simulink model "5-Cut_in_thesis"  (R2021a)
settings: Solver=VariableStepAuto  StartTime=0.0  StopTime=24  RelTol=1e-3
undefined symbols (not defined in the file or in its folder): aubr, tablebr, vubr
libraries: pid_lib x5, Solver_SF x2

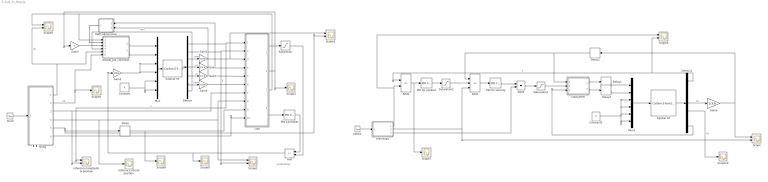
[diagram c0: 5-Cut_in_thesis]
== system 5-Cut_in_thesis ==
  note: 规划接口
  note: understeer
  Add : Sum  Inputs=-+
  Add1 : Sum  Inputs=-++
  Add2 : Sum  Inputs=-+
  Add3 : Sum
  Clock : Clock
  Clock1 : Clock
  Constant : Constant  Value=0
  Constant2 : Constant  Value=0
  Delay : Delay  DelayLength=10
  Delay1 : Delay  DelayLength=100
  Delay2 : Delay  DelayLength=10
  Delay3 : Delay  DelayLength=100
  Demux : Demux  Outputs=7
  Demux1 : Demux  Outputs=7
  EgoCar SF : Solver_SF/CarSim S-Function  Priority=1  SIMFILE=Cut_in_Ego_Car.sim
  Gain : Gain  Gain=1/3.6
  Gain1 : Gain  Gain=1/3.6
  Gain2 : Gain  Gain=pi/180
  Gain3 : Gain  Gain=180/pi
  Gain4 : Gain  Gain=pi/180
  Gain5 : Gain  Gain=-1
  Gain6 : Gain  Gain=1/3.6
  LQR : Subsystem
  MATLAB Function : MATLAB Function  TreatAsAtomicUnit=on
  Mux : Mux  Inputs=6
  Mux1 : Mux  Inputs=6
  PID Controller : pid_lib/PID Controller  Controller=PID  Form=Parallel  TimeDomain=Continuous-time  UseExternalTs=off  SampleTime=-1  IntegratorMethod=Forward Euler  FilterMethod=Forward Euler  ControllerParametersSource=internal  P=1  I=0  D=0  UseFilter=on  N=100  TunerSelectOption=Transfer Function Based (PID Tuner App)  InitialConditionSource=internal  InitialConditionForIntegrator=0  InitialConditionForFilter=0  DifferentiatorICPrevScaledInput=0  ExternalReset=none  TrackingMode=off  Kt=1  LimitOutput=off  SatLimitsSource=internal  UpperSaturationLimit=inf  LowerSaturationLimit=-inf  LinearizeAsGain=on  AntiWindupMode=none  Kb=1  POutMin=[]  POutMax=[]  IOutMin=[]  IOutMax=[]  DOutMin=[]  DOutMax=[]  NOutMin=[]  NOutMax=[]  SumOutMin=[]  SumOutMax=[]  SaturationOutMin=[]  SaturationOutMax=[]  PParamMin=[]  PParamMax=[]  IParamMin=[]  IParamMax=[]  DParamMin=[]  DParamMax=[]  NParamMin=[]  NParamMax=[]  KbParamMin=[]  KbParamMax=[]  KtParamMin=[]  KtParamMax=[]  KbOutMin=[]  KbOutMax=[]  KtOutMin=[]  KtOutMax=[]  IntegratorOutMin=[]  IntegratorOutMax=[]  FilterOutMin=[]  FilterOutMax=[]  SumI1OutMin=[]  SumI1OutMax=[]  SumI2OutMin=[]  SumI2OutMax=[]  SumI3OutMin=[]  SumI3OutMax=[]  SumI4OutMin=[]  SumI4OutMax=[]  SumDOutMin=[]  SumDOutMax=[]  DifferentiatorOutMin=[]  DifferentiatorOutMax=[]  FilterDiffOutCoefMin=[]  FilterDiffOutCoefMax=[]  ReciprocalOutMin=[]  ReciprocalOutMax=[]  SumDenOutMin=[]  SumDenOutMax=[]  SumNumOutMin=[]  SumNumOutMax=[]  DivideOutMin=[]  DivideOutMax=[]  UdiffTsProdOutMin=[]  UdiffTsProdOutMax=[]  NTsProdOutMin=[]  NTsProdOutMax=[]  UintegralTsProdOutMin=[]  UintegralTsProdOutMax=[]  UngainTsProdOutMin=[]  UngainTsProdOutMax=[]  IntegratorContinuousStateAttributes=''  IntegratorStateMustResolveToSignalObject=off  IntegratorRTWStateStorageClass=Auto  FilterContinuousStateAttributes=''  FilterStateMustResolveToSignalObject=off  FilterRTWStateStorageClass=Auto  ParallelPVariant=InternalParameters  IdealPVariant=Disabled  IVariant=InternalParameters  DVariant=InternalParameters  IntegratorVariant=Continuous  SatVariant=Disabled  AWVariant=Passthrough  PCopyVariant=Disabled  TRVariant=Disabled  FdbkBlocksVariant=Forward  IdealPFdbkVariant=Disabled  SatFdbkVariant=Disabled  DerivativeFilterVariant=ContFilter  NVariant=InternalParameters  NCopyVariant=Disabled  FilterICVariant=InternalICsFilter  IntegratorICVariant=InternalICs  ExternalResetVariant=Disabled  TRSumVariant=Passthrough  SumFdbkVariant=Disabled  SumVariant=Sum_PID  TsampFilterVariant=InternalTs  TsampNgainVariant=Passthrough  TsampIntegralVariant=Passthrough  ExternalSaturationOutDataTypeStr=Inherit: Same as second input
  PID for position : pid_lib/PID Controller  Controller=PID  Form=Parallel  TimeDomain=Continuous-time  UseExternalTs=off  SampleTime=-1  IntegratorMethod=Forward Euler  FilterMethod=Forward Euler  ControllerParametersSource=internal  P=2  I=0  D=0.1  UseFilter=on  N=30  TunerSelectOption=Transfer Function Based (PID Tuner App)  InitialConditionSource=internal  InitialConditionForIntegrator=0  InitialConditionForFilter=0  DifferentiatorICPrevScaledInput=0  ExternalReset=none  TrackingMode=off  Kt=1  LimitOutput=off  SatLimitsSource=internal  UpperSaturationLimit=inf  LowerSaturationLimit=-inf  LinearizeAsGain=on  AntiWindupMode=none  Kb=1  POutMin=[]  POutMax=[]  IOutMin=[]  IOutMax=[]  DOutMin=[]  DOutMax=[]  NOutMin=[]  NOutMax=[]  SumOutMin=[]  SumOutMax=[]  SaturationOutMin=[]  SaturationOutMax=[]  PParamMin=[]  PParamMax=[]  IParamMin=[]  IParamMax=[]  DParamMin=[]  DParamMax=[]  NParamMin=[]  NParamMax=[]  KbParamMin=[]  KbParamMax=[]  KtParamMin=[]  KtParamMax=[]  KbOutMin=[]  KbOutMax=[]  KtOutMin=[]  KtOutMax=[]  IntegratorOutMin=[]  IntegratorOutMax=[]  FilterOutMin=[]  FilterOutMax=[]  SumI1OutMin=[]  SumI1OutMax=[]  SumI2OutMin=[]  SumI2OutMax=[]  SumI3OutMin=[]  SumI3OutMax=[]  SumI4OutMin=[]  SumI4OutMax=[]  SumDOutMin=[]  SumDOutMax=[]  DifferentiatorOutMin=[]  DifferentiatorOutMax=[]  FilterDiffOutCoefMin=[]  FilterDiffOutCoefMax=[]  ReciprocalOutMin=[]  ReciprocalOutMax=[]  SumDenOutMin=[]  SumDenOutMax=[]  SumNumOutMin=[]  SumNumOutMax=[]  DivideOutMin=[]  DivideOutMax=[]  UdiffTsProdOutMin=[]  UdiffTsProdOutMax=[]  NTsProdOutMin=[]  NTsProdOutMax=[]  UintegralTsProdOutMin=[]  UintegralTsProdOutMax=[]  UngainTsProdOutMin=[]  UngainTsProdOutMax=[]  IntegratorContinuousStateAttributes=''  IntegratorStateMustResolveToSignalObject=off  IntegratorRTWStateStorageClass=Auto  FilterContinuousStateAttributes=''  FilterStateMustResolveToSignalObject=off  FilterRTWStateStorageClass=Auto  ParallelPVariant=InternalParameters  IdealPVariant=Disabled  IVariant=InternalParameters  DVariant=InternalParameters  IntegratorVariant=Continuous  SatVariant=Disabled  AWVariant=Passthrough  PCopyVariant=Disabled  TRVariant=Disabled  FdbkBlocksVariant=Forward  IdealPFdbkVariant=Disabled  SatFdbkVariant=Disabled  DerivativeFilterVariant=ContFilter  NVariant=InternalParameters  NCopyVariant=Disabled  FilterICVariant=InternalICsFilter  IntegratorICVariant=InternalICs  ExternalResetVariant=Disabled  TRSumVariant=Passthrough  SumFdbkVariant=Disabled  SumVariant=Sum_PID  TsampFilterVariant=InternalTs  TsampNgainVariant=Passthrough  TsampIntegralVariant=Passthrough  ExternalSaturationOutDataTypeStr=Inherit: Same as second input
  PID for velocity : pid_lib/PID Controller  Controller=PID  Form=Parallel  TimeDomain=Continuous-time  UseExternalTs=off  SampleTime=-1  IntegratorMethod=Forward Euler  FilterMethod=Forward Euler  ControllerParametersSource=internal  P=1  I=0  D=0.1  UseFilter=on  N=30  TunerSelectOption=Transfer Function Based (PID Tuner App)  InitialConditionSource=internal  InitialConditionForIntegrator=0  InitialConditionForFilter=0  DifferentiatorICPrevScaledInput=0  ExternalReset=none  TrackingMode=off  Kt=1  LimitOutput=off  SatLimitsSource=internal  UpperSaturationLimit=inf  LowerSaturationLimit=-inf  LinearizeAsGain=on  AntiWindupMode=none  Kb=1  POutMin=[]  POutMax=[]  IOutMin=[]  IOutMax=[]  DOutMin=[]  DOutMax=[]  NOutMin=[]  NOutMax=[]  SumOutMin=[]  SumOutMax=[]  SaturationOutMin=[]  SaturationOutMax=[]  PParamMin=[]  PParamMax=[]  IParamMin=[]  IParamMax=[]  DParamMin=[]  DParamMax=[]  NParamMin=[]  NParamMax=[]  KbParamMin=[]  KbParamMax=[]  KtParamMin=[]  KtParamMax=[]  KbOutMin=[]  KbOutMax=[]  KtOutMin=[]  KtOutMax=[]  IntegratorOutMin=[]  IntegratorOutMax=[]  FilterOutMin=[]  FilterOutMax=[]  SumI1OutMin=[]  SumI1OutMax=[]  SumI2OutMin=[]  SumI2OutMax=[]  SumI3OutMin=[]  SumI3OutMax=[]  SumI4OutMin=[]  SumI4OutMax=[]  SumDOutMin=[]  SumDOutMax=[]  DifferentiatorOutMin=[]  DifferentiatorOutMax=[]  FilterDiffOutCoefMin=[]  FilterDiffOutCoefMax=[]  ReciprocalOutMin=[]  ReciprocalOutMax=[]  SumDenOutMin=[]  SumDenOutMax=[]  SumNumOutMin=[]  SumNumOutMax=[]  DivideOutMin=[]  DivideOutMax=[]  UdiffTsProdOutMin=[]  UdiffTsProdOutMax=[]  NTsProdOutMin=[]  NTsProdOutMax=[]  UintegralTsProdOutMin=[]  UintegralTsProdOutMax=[]  UngainTsProdOutMin=[]  UngainTsProdOutMax=[]  IntegratorContinuousStateAttributes=''  IntegratorStateMustResolveToSignalObject=off  IntegratorRTWStateStorageClass=Auto  FilterContinuousStateAttributes=''  FilterStateMustResolveToSignalObject=off  FilterRTWStateStorageClass=Auto  ParallelPVariant=InternalParameters  IdealPVariant=Disabled  IVariant=InternalParameters  DVariant=InternalParameters  IntegratorVariant=Continuous  SatVariant=Disabled  AWVariant=Passthrough  PCopyVariant=Disabled  TRVariant=Disabled  FdbkBlocksVariant=Forward  IdealPFdbkVariant=Disabled  SatFdbkVariant=Disabled  DerivativeFilterVariant=ContFilter  NVariant=InternalParameters  NCopyVariant=Disabled  FilterICVariant=InternalICsFilter  IntegratorICVariant=InternalICs  ExternalResetVariant=Disabled  TRSumVariant=Passthrough  SumFdbkVariant=Disabled  SumVariant=Sum_PID  TsampFilterVariant=InternalTs  TsampNgainVariant=Passthrough  TsampIntegralVariant=Passthrough  ExternalSaturationOutDataTypeStr=Inherit: Same as second input
  Saturation : Saturate  UpperLimit=1  LowerLimit=-1
  Saturation1 : Saturate  UpperLimit=5  LowerLimit=-8
  Saturation2 : Saturate  UpperLimit=10  LowerLimit=-10
  Scope{,1..2,5..6} (5 alike) : Scope  NumInputPorts=2
  Scope{3..4,7..10} (6 alike) : Scope
  SideCar SF : Solver_SF/CarSim S-Function  Priority=1  SIMFILE=SideCar.sim
  Subsystem : Subsystem
  double_pid_controller : Subsystem
  planning : MATLAB Function  TreatAsAtomicUnit=on
  planning1 : MATLAB Function  TreatAsAtomicUnit=on
  reference lateral position : Scope
  reference longitudinal position : Scope  NumInputPorts=2
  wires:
  planning/6(kr) -> LQR/10(kappar)
  Demux/1 -> reference longitudinal position/1, LQR/1(x)  "x"
  LQR/4(ed) -> PID Controller/1
  Gain2/1 -> Scope2/1, LQR/3(phi)
  Demux/4 -> Gain/1  "vx"
  Demux/2 -> Scope1/2, LQR/2(y)  "y"
  PID Controller/1 -> Add/1
  Add/1 -> Scope9/1, Gain3/1
  Saturation/1 -> Add/2
  Constant/1 -> Mux/5, Mux/6
  planning/1(vp) -> Scope5/2, double_pid_controller/5(vp)  "vp"
  planning/2(ap) -> double_pid_controller/6(ap), Scope4/1  "ap"
  LQR/3(s_dot) -> Scope5/1, double_pid_controller/1(s_dot)
  LQR/1(angle) -> Saturation/1
  Clock/1 -> planning/1(t)
  LQR/2(es) -> Scope3/1, Gain5/1
  Mux/1 -> SideCar SF/1
  double_pid_controller/2(Out2) -> Mux/2
  Gain/1 -> LQR/4(vx), MATLAB Function/1(vx)
  Demux/6 -> Gain4/1  "dyaw"
  Demux/3 -> Gain2/1  "yaw"
  Gain1/1 -> LQR/5(vy), MATLAB Function/2(vy)
  Demux/5 -> Gain1/1  "vy"
  Demux/7 -> double_pid_controller/4(rpm)  "rpm"
  Gain4/1 -> LQR/6(phi_dot)
  double_pid_controller/1(Out1) -> Mux/1
  Gain3/1 -> Mux/4, Mux/3
  MATLAB Function/1(v) -> double_pid_controller/2(v)
  Gain5/1 -> double_pid_controller/3(es)
  planning/5(thetar) -> Scope2/2, Delay/1
  planning/4(yr) -> LQR/8(yr), Scope1/1, reference lateral position/1
  planning/3(xr) -> reference longitudinal position/2, LQR/7(xr)
  SideCar SF/1 -> Demux/1
  Add1/1 -> PID for velocity/1
  Demux1/4 -> Gain6/1  "Vx"
  Clock1/1 -> planning1/1(t)
  Gain6/1 -> Scope/1, Delay2/1
  Delay2/1 -> Add1/1, Subsystem/1(v)
  Mux1/1 -> EgoCar SF/1
  Constant2/1 -> Mux1/3, Mux1/4, Mux1/6, Mux1/5
  EgoCar SF/1 -> Demux1/1
  planning1/2(vp) -> Scope/2, Add1/3
  Saturation1/1 -> Subsystem/2(a)
  Demux1/7 -> Subsystem/3(rpm)
  Subsystem/1(torque) -> Delay1/1
  Subsystem/2(brake) -> Delay3/1
  Add2/1 -> Scope7/1, PID for position/1
  planning1/1(xr) -> Scope6/1, Add2/2
  Demux1/1 -> Scope6/2, Add2/1  "x"
  PID for velocity/1 -> Add3/1
  Add3/1 -> Saturation1/1
  planning1/3(ap) -> Add3/2
  PID for position/1 -> Saturation2/1
  Saturation2/1 -> Add1/2
  Delay1/1 -> Mux1/1
  Delay3/1 -> Mux1/2
  Delay/1 -> LQR/9(thetar), Scope8/1
  Demux1/5 -> Scope10/1  "vy"
  Demux1/3 -> ?  "yaw"
  Demux1/6 -> ?  "dyaw"

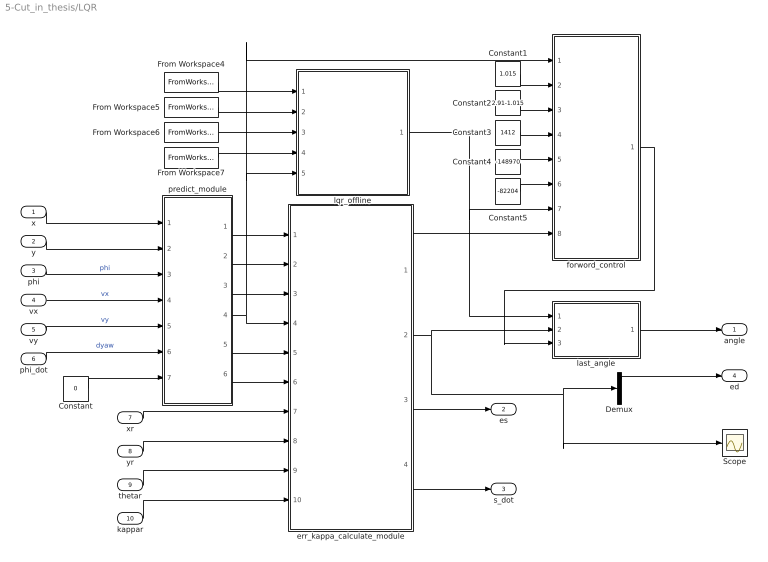
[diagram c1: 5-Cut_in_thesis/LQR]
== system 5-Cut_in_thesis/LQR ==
  x : Inport
  y : Inport  Port=2
  phi : Inport  Port=3
  vx : Inport  Port=4
  vy : Inport  Port=5
  phi_dot : Inport  Port=6
  xr : Inport  Port=7
  yr : Inport  Port=8
  thetar : Inport  Port=9
  kappar : Inport  Port=10
  Constant : Constant  Value=0
  Constant1 : Constant  Value=1.015
  Constant2 : Constant  Value=2.91-1.015
  Constant3 : Constant  Value=1412
  Constant4 : Constant  Value=-148970
  Constant5 : Constant  Value=-82204
  Demux : Demux
  From Workspace4 : FromWorkspace  VariableName=k1
  From Workspace5 : FromWorkspace  VariableName=k2
  From Workspace6 : FromWorkspace  VariableName=k3
  From Workspace7 : FromWorkspace  VariableName=k4
  Scope : Scope
  err_kappa_calculate_module : MATLAB Function  TreatAsAtomicUnit=on
  forword_control : MATLAB Function  TreatAsAtomicUnit=on
  last_angle : MATLAB Function  TreatAsAtomicUnit=on
  lqr_offline : MATLAB Function  TreatAsAtomicUnit=on
  predict_module : MATLAB Function  TreatAsAtomicUnit=on
  angle : Outport  VectorParamsAs1DForOutWhenUnconnected=off
  es : Outport  Port=2  VectorParamsAs1DForOutWhenUnconnected=off
  s_dot : Outport  Port=3  VectorParamsAs1DForOutWhenUnconnected=off
  ed : Outport  Port=4  VectorParamsAs1DForOutWhenUnconnected=off
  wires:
  From Workspace7/1 -> lqr_offline/4(k4)
  vy/1 -> predict_module/5(vy)  "vy"
  From Workspace6/1 -> lqr_offline/3(k3)
  x/1 -> predict_module/1(x)
  lqr_offline/1(k) -> last_angle/1(k), forword_control/7(k)
  predict_module/2(pre_y) -> err_kappa_calculate_module/2(y)
  err_kappa_calculate_module/1(kr) -> forword_control/8(kr)
  forword_control/1(forword_angle) -> last_angle/3(forword_angle)
  predict_module/4(pre_vx) -> lqr_offline/5(vx), forword_control/1(vx), err_kappa_calculate_module/4(vx)
  phi_dot/1 -> predict_module/6(phi_dot)  "dyaw"
  last_angle/1(angle) -> angle/1
  From Workspace5/1 -> lqr_offline/2(k2)
  vx/1 -> predict_module/4(vx)  "vx"
  y/1 -> predict_module/2(y)
  phi/1 -> predict_module/3(phi)  "phi"
  Constant/1 -> predict_module/7(ts)
  From Workspace4/1 -> lqr_offline/1(k1)
  predict_module/1(pre_x) -> err_kappa_calculate_module/1(x)
  predict_module/5(pre_vy) -> err_kappa_calculate_module/5(vy)
  predict_module/6(pre_phi_dot) -> err_kappa_calculate_module/6(phi_dot)
  predict_module/3(pre_phi) -> err_kappa_calculate_module/3(phi)
  Constant1/1 -> forword_control/2(a)
  Constant2/1 -> forword_control/3(b)
  Constant3/1 -> forword_control/4(m)
  Constant4/1 -> forword_control/5(cf)
  xr/1 -> err_kappa_calculate_module/7(xr)
  yr/1 -> err_kappa_calculate_module/8(yr)
  thetar/1 -> err_kappa_calculate_module/9(thetar)
  kappar/1 -> err_kappa_calculate_module/10(kappar)
  err_kappa_calculate_module/3(es) -> es/1
  err_kappa_calculate_module/4(s_dot) -> s_dot/1
  Constant5/1 -> forword_control/6(cr)
  Demux/1 -> ed/1
  err_kappa_calculate_module/2(err) -> Scope/1, Demux/1, last_angle/2(err)

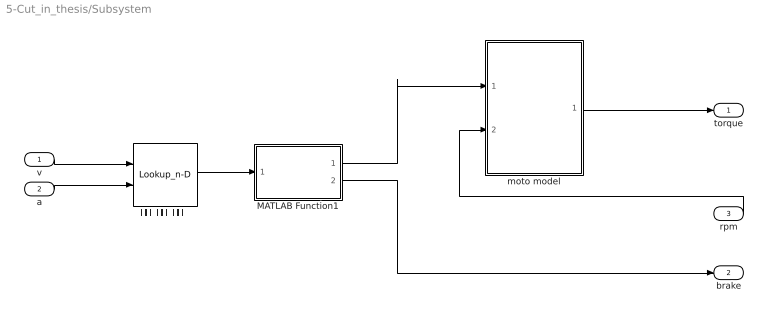
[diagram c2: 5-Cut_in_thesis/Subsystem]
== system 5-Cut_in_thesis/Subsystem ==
  v : Inport
  a : Inport  Port=2
  rpm : Inport  Port=3
  MATLAB Function1 : MATLAB Function  TreatAsAtomicUnit=on
  moto model : MATLAB Function  TreatAsAtomicUnit=on
  油门刹车合并标定表 : Lookup_n-D  BreakpointsForDimension1=vubr  BreakpointsForDimension2=aubr  Table=tablebr  InternalRulePriority=Speed  RndMeth=Simplest
  torque : Outport
  brake : Outport  Port=2
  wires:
  rpm/1 -> moto model/2(rpm)
  油门刹车合并标定表/1 -> MATLAB Function1/1(x)
  MATLAB Function1/1(thr) -> moto model/1(thr)
  MATLAB Function1/2(brake) -> brake/1
  v/1 -> 油门刹车合并标定表/1
  moto model/1(torque) -> torque/1
  a/1 -> 油门刹车合并标定表/2

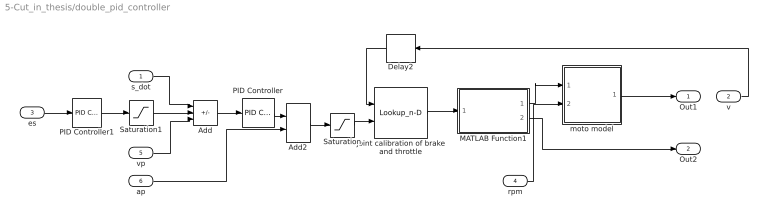
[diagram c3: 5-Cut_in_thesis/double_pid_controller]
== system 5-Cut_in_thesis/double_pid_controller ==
  s_dot : Inport
  v : Inport  Port=2
  es : Inport  Port=3
  rpm : Inport  Port=4
  vp : Inport  Port=5
  ap : Inport  Port=6
  Add : Sum  Inputs=-++
  Add2 : Sum
  Delay2 : Delay  DelayLength=1
  MATLAB Function1 : MATLAB Function  TreatAsAtomicUnit=on
  PID Controller : pid_lib/PID Controller  Controller=PID  Form=Parallel  TimeDomain=Continuous-time  UseExternalTs=off  SampleTime=-1  IntegratorMethod=Forward Euler  FilterMethod=Forward Euler  ControllerParametersSource=internal  P=3  I=0  D=0.1  UseFilter=on  N=30  TunerSelectOption=Transfer Function Based (PID Tuner App)  InitialConditionSource=internal  InitialConditionForIntegrator=0  InitialConditionForFilter=0  DifferentiatorICPrevScaledInput=0  ExternalReset=none  TrackingMode=off  Kt=1  LimitOutput=off  SatLimitsSource=internal  UpperSaturationLimit=inf  LowerSaturationLimit=-inf  LinearizeAsGain=on  AntiWindupMode=none  Kb=1  POutMin=[]  POutMax=[]  IOutMin=[]  IOutMax=[]  DOutMin=[]  DOutMax=[]  NOutMin=[]  NOutMax=[]  SumOutMin=[]  SumOutMax=[]  SaturationOutMin=[]  SaturationOutMax=[]  PParamMin=[]  PParamMax=[]  IParamMin=[]  IParamMax=[]  DParamMin=[]  DParamMax=[]  NParamMin=[]  NParamMax=[]  KbParamMin=[]  KbParamMax=[]  KtParamMin=[]  KtParamMax=[]  KbOutMin=[]  KbOutMax=[]  KtOutMin=[]  KtOutMax=[]  IntegratorOutMin=[]  IntegratorOutMax=[]  FilterOutMin=[]  FilterOutMax=[]  SumI1OutMin=[]  SumI1OutMax=[]  SumI2OutMin=[]  SumI2OutMax=[]  SumI3OutMin=[]  SumI3OutMax=[]  SumI4OutMin=[]  SumI4OutMax=[]  SumDOutMin=[]  SumDOutMax=[]  DifferentiatorOutMin=[]  DifferentiatorOutMax=[]  FilterDiffOutCoefMin=[]  FilterDiffOutCoefMax=[]  ReciprocalOutMin=[]  ReciprocalOutMax=[]  SumDenOutMin=[]  SumDenOutMax=[]  SumNumOutMin=[]  SumNumOutMax=[]  DivideOutMin=[]  DivideOutMax=[]  UdiffTsProdOutMin=[]  UdiffTsProdOutMax=[]  NTsProdOutMin=[]  NTsProdOutMax=[]  UintegralTsProdOutMin=[]  UintegralTsProdOutMax=[]  UngainTsProdOutMin=[]  UngainTsProdOutMax=[]  IntegratorContinuousStateAttributes=''  IntegratorStateMustResolveToSignalObject=off  IntegratorRTWStateStorageClass=Auto  FilterContinuousStateAttributes=''  FilterStateMustResolveToSignalObject=off  FilterRTWStateStorageClass=Auto  ParallelPVariant=InternalParameters  IdealPVariant=Disabled  IVariant=InternalParameters  DVariant=InternalParameters  IntegratorVariant=Continuous  SatVariant=Disabled  AWVariant=Passthrough  PCopyVariant=Disabled  TRVariant=Disabled  FdbkBlocksVariant=Forward  IdealPFdbkVariant=Disabled  SatFdbkVariant=Disabled  DerivativeFilterVariant=ContFilter  NVariant=InternalParameters  NCopyVariant=Disabled  FilterICVariant=InternalICsFilter  IntegratorICVariant=InternalICs  ExternalResetVariant=Disabled  TRSumVariant=Passthrough  SumFdbkVariant=Disabled  SumVariant=Sum_PID  TsampFilterVariant=InternalTs  TsampNgainVariant=Passthrough  TsampIntegralVariant=Passthrough  ExternalSaturationOutDataTypeStr=Inherit: Same as second input
  PID Controller1 : pid_lib/PID Controller  Controller=PID  Form=Parallel  TimeDomain=Continuous-time  UseExternalTs=off  SampleTime=-1  IntegratorMethod=Forward Euler  FilterMethod=Forward Euler  ControllerParametersSource=internal  P=3  I=0  D=0.1  UseFilter=on  N=30  TunerSelectOption=Transfer Function Based (PID Tuner App)  InitialConditionSource=internal  InitialConditionForIntegrator=0  InitialConditionForFilter=0  DifferentiatorICPrevScaledInput=0  ExternalReset=none  TrackingMode=off  Kt=1  LimitOutput=off  SatLimitsSource=internal  UpperSaturationLimit=inf  LowerSaturationLimit=-inf  LinearizeAsGain=on  AntiWindupMode=none  Kb=1  POutMin=[]  POutMax=[]  IOutMin=[]  IOutMax=[]  DOutMin=[]  DOutMax=[]  NOutMin=[]  NOutMax=[]  SumOutMin=[]  SumOutMax=[]  SaturationOutMin=[]  SaturationOutMax=[]  PParamMin=[]  PParamMax=[]  IParamMin=[]  IParamMax=[]  DParamMin=[]  DParamMax=[]  NParamMin=[]  NParamMax=[]  KbParamMin=[]  KbParamMax=[]  KtParamMin=[]  KtParamMax=[]  KbOutMin=[]  KbOutMax=[]  KtOutMin=[]  KtOutMax=[]  IntegratorOutMin=[]  IntegratorOutMax=[]  FilterOutMin=[]  FilterOutMax=[]  SumI1OutMin=[]  SumI1OutMax=[]  SumI2OutMin=[]  SumI2OutMax=[]  SumI3OutMin=[]  SumI3OutMax=[]  SumI4OutMin=[]  SumI4OutMax=[]  SumDOutMin=[]  SumDOutMax=[]  DifferentiatorOutMin=[]  DifferentiatorOutMax=[]  FilterDiffOutCoefMin=[]  FilterDiffOutCoefMax=[]  ReciprocalOutMin=[]  ReciprocalOutMax=[]  SumDenOutMin=[]  SumDenOutMax=[]  SumNumOutMin=[]  SumNumOutMax=[]  DivideOutMin=[]  DivideOutMax=[]  UdiffTsProdOutMin=[]  UdiffTsProdOutMax=[]  NTsProdOutMin=[]  NTsProdOutMax=[]  UintegralTsProdOutMin=[]  UintegralTsProdOutMax=[]  UngainTsProdOutMin=[]  UngainTsProdOutMax=[]  IntegratorContinuousStateAttributes=''  IntegratorStateMustResolveToSignalObject=off  IntegratorRTWStateStorageClass=Auto  FilterContinuousStateAttributes=''  FilterStateMustResolveToSignalObject=off  FilterRTWStateStorageClass=Auto  ParallelPVariant=InternalParameters  IdealPVariant=Disabled  IVariant=InternalParameters  DVariant=InternalParameters  IntegratorVariant=Continuous  SatVariant=Disabled  AWVariant=Passthrough  PCopyVariant=Disabled  TRVariant=Disabled  FdbkBlocksVariant=Forward  IdealPFdbkVariant=Disabled  SatFdbkVariant=Disabled  DerivativeFilterVariant=ContFilter  NVariant=InternalParameters  NCopyVariant=Disabled  FilterICVariant=InternalICsFilter  IntegratorICVariant=InternalICs  ExternalResetVariant=Disabled  TRSumVariant=Passthrough  SumFdbkVariant=Disabled  SumVariant=Sum_PID  TsampFilterVariant=InternalTs  TsampNgainVariant=Passthrough  TsampIntegralVariant=Passthrough  ExternalSaturationOutDataTypeStr=Inherit: Same as second input
  Saturation : Saturate  UpperLimit=5  LowerLimit=-8
  Saturation1 : Saturate  UpperLimit=10  LowerLimit=-10
  joint calibration of brake and throttle : Lookup_n-D  BreakpointsForDimension1=vubr  BreakpointsForDimension2=aubr  Table=tablebr  InternalRulePriority=Speed  RndMeth=Simplest
  moto model : MATLAB Function  TreatAsAtomicUnit=on
  Out1 : Outport  VectorParamsAs1DForOutWhenUnconnected=off
  Out2 : Outport  Port=2  VectorParamsAs1DForOutWhenUnconnected=off
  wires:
  v/1 -> Delay2/1
  ap/1 -> Add2/2
  Add2/1 -> Saturation/1
  Saturation/1 -> joint calibration of brake and throttle/2
  Delay2/1 -> joint calibration of brake and throttle/1
  joint calibration of brake and throttle/1 -> MATLAB Function1/1(x)
  Add/1 -> PID Controller/1
  PID Controller/1 -> Add2/1
  MATLAB Function1/1(thr) -> moto model/1(thr)
  PID Controller1/1 -> Saturation1/1
  moto model/1(torque) -> Out1/1
  MATLAB Function1/2(brake) -> Out2/1
  vp/1 -> Add/3
  es/1 -> PID Controller1/1
  s_dot/1 -> Add/1
  rpm/1 -> moto model/2(rpm)
  Saturation1/1 -> Add/2

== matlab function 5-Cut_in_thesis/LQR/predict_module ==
function [pre_x,pre_y,pre_phi,pre_vx,pre_vy,pre_phi_dot] = fcn(x,y,phi,vx,vy,phi_dot,ts)
    pre_x=x+vx*ts*cos(phi)-vy*ts*sin(phi);
    pre_y=y+vy*ts*cos(phi)+vx*ts*sin(phi);
    pre_phi=phi+phi_dot*ts;
    pre_vx=vx;
    pre_vy=vy;
    pre_phi_dot=phi_dot;
end

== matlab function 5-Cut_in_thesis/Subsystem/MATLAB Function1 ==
function [thr,brake] = fcn(x)
    %正数代表油门，负数代表刹车
    %不允许同时踩油门和刹车
    if x>=0
        thr=x;
        brake=0;
    else
        thr=0;
        brake=-x;
    end

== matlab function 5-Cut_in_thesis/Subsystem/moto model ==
function torque = fcn(thr,rpm)
Tmax=380*thr;
    if (rpm<=4523)
        torque=Tmax;
    else
        torque=Tmax*4523/rpm;
    end
end

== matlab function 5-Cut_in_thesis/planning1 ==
 function [xr,vp,ap] = fcn(t)
   dx=91;
    dy=1.875;
    T=24;
    xstart=[0,6,0];
    xend=[dx,1.5,0];
    ystart=[1.875,0,0];
    yend=[1.875,0,0];
    a=zeros(1,6);
    b=zeros(1,6);
    
    a(1)=xstart(1);
    a(2)=xstart(2);
    a(3)=xstart(3)/2;
    A1=[T^3,T^4,T^5;
        3*T^2,4*T^3,5*T^4;
        6*T,12*T^2,20*T^3];
    B1=[xend(1)-a(1)-a(2)*T-a(3)*T^2;
        xend(2)-a(2)-2*a(3)*T;
        xend(3)-2*a(3)];
    xs=inv(A1)*B1;
    a(4)=xs(1);
    a(5)=xs(2);
    a(6)=xs(3);
    b(1)=ystart(1);
    b(2)=ystart(2);
    b(3)=ystart(3)/2;
    A2=[dx^3,dx^4,dx^5;
        3*dx^2,4*dx^3,5*dx^4;
        6*dx,12*dx^2,20*dx^3];
    B2=[yend(1)-b(1)-b(2)*dx-b(3)*dx^2;
        yend(2)-b(2)-2*b(3)*dx;
        yend(3)-2*b(3)];
    ys=inv(A2)*B2;
    b(4)=ys(1);
    b(5)=ys(2);
    b(6)=ys(3);
    xr=a(1)+a(2)*t+a(3)*t^2+a(4)*t^3+a(5)*t^4+a(6)*t^5;
    yr=b(1)+b(2)*xr+b(3)*xr^2+b(4)*xr^3+b(5)*xr^4+b(6)*xr^5;
    xr_dot=a(2)+2*a(3)*t+3*a(4)*t^2+4*a(5)*t^3+5*a(6)*t^4;
    yr_dx=b(2)+2*b(3)*xr+3*b(4)*xr^2+4*b(5)*xr^3+5*b(6)*xr^4;
    yr_dot=yr_dx*xr_dot;
    thetar=atan(yr_dx);
    xr_dot2=2*a(3)+6*a(4)*t+12*a(5)*t^2+20*a(6)*t^3;
    yr_dx2=2*b(3)+6*b(4)*xr+12*b(5)*xr^2+20*b(6)*xr^3;
    yr_dot2=yr_dx2*xr_dot^2+yr_dx*xr_dot2;
    kr=yr_dx2/((1+yr_dx^2)^1.5);
    vp=sqrt(xr_dot^2+yr_dot^2);
    if xr_dot2>=0
        ap=sqrt(xr_dot2^2+yr_dot2^2);
    else
        ap=-sqrt(xr_dot2^2+yr_dot2^2);
    end

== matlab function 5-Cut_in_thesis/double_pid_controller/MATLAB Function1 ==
function [thr,brake] = fcn(x)
    %正数代表油门，负数代表刹车
    %不允许同时踩油门和刹车
    if x>=0
        thr=x;
        brake=0;
    else
        thr=0;
        brake=-x;
    end

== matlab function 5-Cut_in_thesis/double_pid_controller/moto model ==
function torque = fcn(thr,rpm)
Tmax=380*thr;
    if (rpm<=4523)
        torque=Tmax;
    else
        torque=Tmax*4523/rpm;
    end
end

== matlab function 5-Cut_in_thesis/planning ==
function [vp,ap,xr,yr,thetar,kr] = fcn(t)
    if t <= 6
        dx=28;
        dy=0;
        T=6;
        xstart=[0,4,0];
        xend=[dx,5.4,0];
        ystart=[-1.875,0,0];
        yend=[-1.875,0,0];
        a=zeros(1,6);
        b=zeros(1,6);
    
        a(1)=xstart(1);
        a(2)=xstart(2);
        a(3)=xstart(3)/2;
        A1=[T^3,T^4,T^5;
            3*T^2,4*T^3,5*T^4;
            6*T,12*T^2,20*T^3];
        B1=[xend(1)-a(1)-a(2)*T-a(3)*T^2;
            xend(2)-a(2)-2*a(3)*T;
            xend(3)-2*a(3)];
        xs=inv(A1)*B1;
        a(4)=xs(1);
        a(5)=xs(2);
        a(6)=xs(3);
        b(1)=ystart(1);
        b(2)=ystart(2);
        b(3)=ystart(3)/2;
        A2=[dx^3,dx^4,dx^5;
            3*dx^2,4*dx^3,5*dx^4;
            6*dx,12*dx^2,20*dx^3];
        B2=[yend(1)-b(1)-b(2)*dx-b(3)*dx^2;
            yend(2)-b(2)-2*b(3)*dx;
            yend(3)-2*b(3)];
        ys=inv(A2)*B2;
        b(4)=ys(1);
        b(5)=ys(2);
        b(6)=ys(3);
        xr=a(1)+a(2)*t+a(3)*t^2+a(4)*t^3+a(5)*t^4+a(6)*t^5;
        yr=b(1)+b(2)*xr+b(3)*xr^2+b(4)*xr^3+b(5)*xr^4+b(6)*xr^5;
        xr_dot=a(2)+2*a(3)*t+3*a(4)*t^2+4*a(5)*t^3+5*a(6)*t^4;
        yr_dx=b(2)+2*b(3)*xr+3*b(4)*xr^2+4*b(5)*xr^3+5*b(6)*xr^4;
        yr_dot=yr_dx*xr_dot;
        thetar=atan(yr_dx);
        xr_dot2=2*a(3)+6*a(4)*t+12*a(5)*t^2+20*a(6)*t^3;
        yr_dx2=2*b(3)+6*b(4)*xr+12*b(5)*xr^2+20*b(6)*xr^3;
        yr_dot2=yr_dx2*xr_dot^2+yr_dx*xr_dot2;
        kr=yr_dx2/((1+yr_dx^2)^1.5);
        vp=sqrt(xr_dot^2+yr_dot^2);
        if xr_dot2>=0
            ap=sqrt(xr_dot2^2+yr_dot2^2);
        else
            ap=-sqrt(xr_dot2^2+yr_dot2^2);
        end
        xr = xr + 8;
    elseif t>6 && t <=10
        dx=22;
        dy=-1.875;
        T=4;
        xstart=[0,5.4,0];
        xend=[dx,5.4,0];
        ystart=[-1.875,0,0];
        yend=[dy,0,0];
        a=zeros(1,6);
        b=zeros(1,6);
    
        a(1)=xstart(1);
        a(2)=xstart(2);
        a(3)=xstart(3)/2;
        A1=[T^3,T^4,T^5;
            3*T^2,4*T^3,5*T^4;
            6*T,12*T^2,20*T^3];
        B1=[xend(1)-a(1)-a(2)*T-a(3)*T^2;
            xend(2)-a(2)-2*a(3)*T;
            xend(3)-2*a(3)];
        xs=inv(A1)*B1;
        a(4)=xs(1);
        a(5)=xs(2);
        a(6)=xs(3);
        b(1)=ystart(1);
        b(2)=ystart(2);
        b(3)=ystart(3)/2;
        A2=[dx^3,dx^4,dx^5;
            3*dx^2,4*dx^3,5*dx^4;
            6*dx,12*dx^2,20*dx^3];
        B2=[yend(1)-b(1)-b(2)*dx-b(3)*dx^2;
            yend(2)-b(2)-2*b(3)*dx;
            yend(3)-2*b(3)];
        ys=inv(A2)*B2;
        b(4)=ys(1);
        b(5)=ys(2);
        b(6)=ys(3);
        xr=a(1)+a(2)*(t-6)+a(3)*(t-6)^2+a(4)*(t-6)^3+a(5)*(t-6)^4+a(6)*(t-6)^5;
        yr=b(1)+b(2)*xr+b(3)*xr^2+b(4)*xr^3+b(5)*xr^4+b(6)*xr^5;
        xr_dot=a(2)+2*a(3)*(t-6)+3*a(4)*(t-6)^2+4*a(5)*(t-6)^3+5*a(6)*(t-6)^4;
        yr_dx=b(2)+2*b(3)*xr+3*b(4)*xr^2+4*b(5)*xr^3+5*b(6)*xr^4;
        yr_dot=yr_dx*xr_dot;
        thetar=atan(yr_dx);
        xr_dot2=2*a(3)+6*a(4)*(t-6)+12*a(5)*(t-6)^2+20*a(6)*(t-6)^3;
        yr_dx2=2*b(3)+6*b(4)*xr+12*b(5)*xr^2+20*b(6)*xr^3;
        yr_dot2=yr_dx2*xr_dot^2+yr_dx*xr_dot2;
        kr=yr_dx2/((1+yr_dx^2)^1.5);
        vp=sqrt(xr_dot^2+yr_dot^2);
        if xr_dot2>=0
            ap=sqrt(xr_dot2^2+yr_dot2^2);
        else
            ap=-sqrt(xr_dot2^2+yr_dot2^2);
        end
        xr = xr + 36;
    elseif t>10 && t <= 20
        dx=53;
        dy=1.875;
        T=10;
        xstart=[0,5.4,0];
        xend=[dx,5.4,0];
        ystart=[-1.875,0,0];
        yend=[dy,0,0];
        a=zeros(1,6);
        b=zeros(1,6);
    
        a(1)=xstart(1);
        a(2)=xstart(2);
        a(3)=xstart(3)/2;
        A1=[T^3,T^4,T^5;
            3*T^2,4*T^3,5*T^4;
            6*T,12*T^2,20*T^3];
        B1=[xend(1)-a(1)-a(2)*T-a(3)*T^2;
            xend(2)-a(2)-2*a(3)*T;
            xend(3)-2*a(3)];
        xs=inv(A1)*B1;
        a(4)=xs(1);
        a(5)=xs(2);
        a(6)=xs(3);
        b(1)=ystart(1);
        b(2)=ystart(2);
        b(3)=ystart(3)/2;
        A2=[dx^3,dx^4,dx^5;
            3*dx^2,4*dx^3,5*dx^4;
            6*dx,12*dx^2,20*dx^3];
        B2=[yend(1)-b(1)-b(2)*dx-b(3)*dx^2;
            yend(2)-b(2)-2*b(3)*dx;
            yend(3)-2*b(3)];
        ys=inv(A2)*B2;
        b(4)=ys(1);
        b(5)=ys(2);
        b(6)=ys(3);
        xr=a(1)+a(2)*(t-10)+a(3)*(t-10)^2+a(4)*(t-10)^3+a(5)*(t-10)^4+a(6)*(t-10)^5;
        yr=b(1)+b(2)*xr+b(3)*xr^2+b(4)*xr^3+b(5)*xr^4+b(6)*xr^5;
        xr_dot=a(2)+2*a(3)*(t-10)+3*a(4)*(t-10)^2+4*a(5)*(t-10)^3+5*a(6)*(t-10)^4;
        yr_dx=b(2)+2*b(3)*xr+3*b(4)*xr^2+4*b(5)*xr^3+5*b(6)*xr^4;
        yr_dot=yr_dx*xr_dot;
        thetar=atan(yr_dx);
        xr_dot2=2*a(3)+6*a(4)*(t-10)+12*a(5)*(t-10)^2+20*a(6)*(t-10)^3;
        yr_dx2=2*b(3)+6*b(4)*xr+12*b(5)*xr^2+20*b(6)*xr^3;
        yr_dot2=yr_dx2*xr_dot^2+yr_dx*xr_dot2;
        kr=yr_dx2/((1+yr_dx^2)^1.5);
        vp=sqrt(xr_dot^2+yr_dot^2);
        if xr_dot2>=0
            ap=sqrt(xr_dot2^2+yr_dot2^2);
        else
            ap=-sqrt(xr_dot2^2+yr_dot2^2);
        end
        xr = xr + 58;
    else
        xr = 111+5.4 * (t-20);
        yr = 1.875;
        vp = 5.4;
        ap = 0;
        kr = 0;
        thetar = 0;
%         dx=25;
%         dy=1.875;
%         T=4;
%         xstart=[0,5.4,0];
%         xend=[dx,5.4,0];
%         ystart=[1.875,0,0];
%         yend=[dy,0,0];
%         a=zeros(1,6);
%         b=zeros(1,6);
%     
%         a(1)=xstart(1);
%         a(2)=xstart(2);
%         a(3)=xstart(3)/2;
%         A1=[T^3,T^4,T^5;
%             3*T^2,4*T^3,5*T^4;
%             6*T,12*T^2,20*T^3];
%         B1=[xend(1)-a(1)-a(2)*T-a(3)*T^2;
%             xend(2)-a(2)-2*a(3)*T;
%             xend(3)-2*a(3)];
%         xs=inv(A1)*B1;
%         a(4)=xs(1);
%         a(5)=xs(2);
%         a(6)=xs(3);
%         b(1)=ystart(1);
%         b(2)=ystart(2);
%         b(3)=ystart(3)/2;
%         A2=[dx^3,dx^4,dx^5;
%             3*dx^2,4*dx^3,5*dx^4;
%             6*dx,12*dx^2,20*dx^3];
%         B2=[yend(1)-b(1)-b(2)*dx-b(3)*dx^2;
%             yend(2)-b(2)-2*b(3)*dx;
%             yend(3)-2*b(3)];
%         ys=inv(A2)*B2;
%         b(4)=ys(1);
%         b(5)=ys(2);
%         b(6)=ys(3);
%         xr=a(1)+a(2)*(t-20)+a(3)*(t-20)^2+a(4)*(t-20)^3+a(5)*(t-20)^4+a(6)*(t-20)^5;
%         yr=b(1)+b(2)*xr+b(3)*xr^2+b(4)*xr^3+b(5)*xr^4+b(6)*xr^5;
%         xr_dot=a(2)+2*a(3)*(t-20)+3*a(4)*(t-20)^2+4*a(5)*(t-20)^3+5*a(6)*(t-20)^4;
%         yr_dx=b(2)+2*b(3)*xr+3*b(4)*xr^2+4*b(5)*xr^3+5*b(6)*xr^4;
%         yr_dot=yr_dx*xr_dot;
%         thetar=atan(yr_dx);
%         xr_dot2=2*a(3)+6*a(4)*(t-20)+12*a(5)*(t-20)^2+20*a(6)*(t-20)^3;
%         yr_dx2=2*b(3)+6*b(4)*xr+12*b(5)*xr^2+20*b(6)*xr^3;
%         yr_dot2=yr_dx2*xr_dot^2+yr_dx*xr_dot2;
%         kr=yr_dx2/((1+yr_dx^2)^1.5);
%         vp=sqrt(xr_dot^2+yr_dot^2);
%         if xr_dot2>=0
%             ap=sqrt(xr_dot2^2+yr_dot2^2);
%         else
%             ap=-sqrt(xr_dot2^2+yr_dot2^2);
%         end
%         xr = xr + 105;
    end
end

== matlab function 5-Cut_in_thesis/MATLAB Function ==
function v = fcn(vx,vy)
    v=sqrt(vx^2+vy^2);

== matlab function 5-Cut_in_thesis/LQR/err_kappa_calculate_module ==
function [kr,err,es,s_dot] = fcn(x,y,phi,vx,vy,phi_dot,xr,yr,thetar,kappar)
    
    tor=[cos(thetar);sin(thetar)];
    nor=[-sin(thetar);cos(thetar)];
    d_err=[x-xr;y-yr];
    ed=nor'*d_err;
    es=tor'*d_err;
    %projection_point_thetar=thetar(dmin);%apollo
    projection_point_thetar=thetar+kappar*es;
    ed_dot=vy*cos(phi-projection_point_thetar)+vx*sin(phi-projection_point_thetar);
    %%%%%%%%%
    ephi=sin(phi-projection_point_thetar);
    %%%%%%%%%
    ss_dot=vx*cos(phi-projection_point_thetar)-vy*sin(phi-projection_point_thetar);
    s_dot=ss_dot/(1-kappar*ed);
    ephi_dot=phi_dot-kappar*s_dot;
    kr=kappar;
    err=[ed;ed_dot;ephi;ephi_dot];
    
    
    
    
    
    
    
    
    
    
    
    


end

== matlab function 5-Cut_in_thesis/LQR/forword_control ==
function forword_angle = fcn(vx,a,b,m,cf,cr,k,kr)
    forword_angle=kr*(a+b-b*k(3)-(m*vx*vx/(a+b))*((b/cf)+(a/cr)*k(3)-(a/cr)));
end

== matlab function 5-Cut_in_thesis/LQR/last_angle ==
function angle = fcn(k,err,forword_angle)

    angle=-k*err+forword_angle;
end

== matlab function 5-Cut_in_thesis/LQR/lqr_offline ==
function k  = fcn(k1,k2,k3,k4,vx)
    if abs(vx)<0.01
        k=[0,0,0,0];
    else
        index=round(vx/0.01);
        k=[k1(index),k2(index),k3(index),k4(index)];
    end
end
